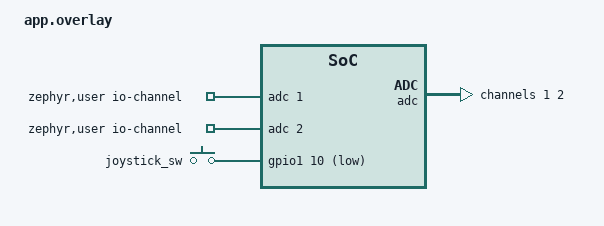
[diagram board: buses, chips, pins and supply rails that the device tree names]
/ {
    aliases {
        joystick-sw = &joystick_sw;
    };

    zephyr,user {
        io-channels = <&adc 1>,
                      <&adc 2>;
    };

    buttons {
        compatible = "gpio-keys";

        joystick_sw: joystick_sw {
            gpios = <&gpio1 10 (GPIO_PULL_UP | GPIO_ACTIVE_LOW)>;
        };
    };
};

&adc {
    status = "okay";
    #address-cells = <1>;
    #size-cells = <0>;

    channel@1 {
        reg = <1>;
        zephyr,gain = "ADC_GAIN_1_6";
        zephyr,reference = "ADC_REF_INTERNAL";
        zephyr,acquisition-time = <ADC_ACQ_TIME_DEFAULT>;
        zephyr,input-positive = <NRF_SAADC_AIN1>;
        zephyr,resolution = <12>;
    };

    channel@2 {
        reg = <2>;
        zephyr,gain = "ADC_GAIN_1_6";
        zephyr,reference = "ADC_REF_INTERNAL";
        zephyr,acquisition-time = <ADC_ACQ_TIME_DEFAULT>;
        zephyr,input-positive = <NRF_SAADC_AIN2>;
        zephyr,resolution = <12>;
    };
};
